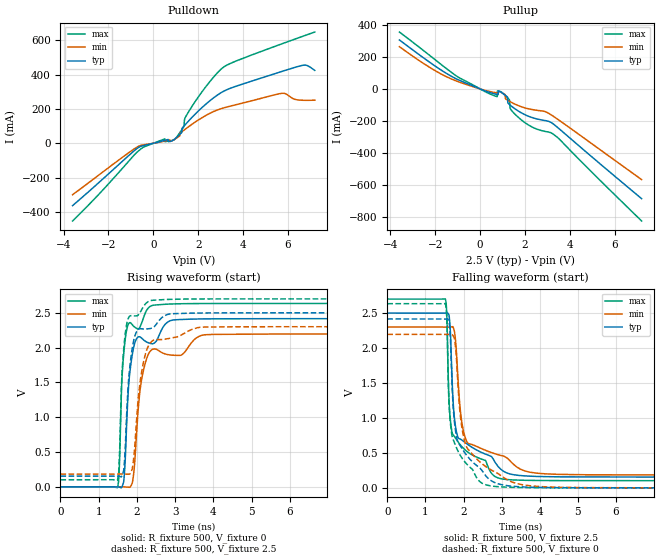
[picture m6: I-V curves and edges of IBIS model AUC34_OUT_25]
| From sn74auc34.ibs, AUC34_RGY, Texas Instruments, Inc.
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[Model]   AUC34_OUT_25
Model_type  Output
Vref =   0
Rref =   500
Cref =   30p
Vmeas =   1.25
| variable   typ   min   max
C_comp   3.5pF   NA   NA
| C_pullup   9.63pF   2.22pF   24.54pF
| C_pulldown   6.92pF   2.05pF   16.12pF
[Temperature Range]   40   100   -40
| Ambient temperature   25   85   -40
[Voltage range]   2.5   2.3   2.7
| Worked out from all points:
|   slope of the pulldown table from 0 to 0.375 V, typ, clamps not added: 30.7 ohm
|   slope of the pullup table from 0 to 0.375 V, typ, clamps not added: 19.1 ohm
|   rising waveform, R_fixture 500, V_fixture 0: 20-80 % time 187ps typ, 255ps min, 137ps max; typ from 0 V to 2.42 V
|   falling waveform, R_fixture 500, V_fixture 2.5: 20-80 % time 434ps typ, 457ps min, 329ps max; typ from 2.5 V to 0.155 V
|   rising waveform, R_fixture 500, V_fixture 2.5: 20-80 % time 190ps typ, 262ps min, 137ps max; typ from 0.154 V to 2.5 V
|   falling waveform, R_fixture 500, V_fixture 0: 20-80 % time 388ps typ, 478ps min, 277ps max; typ from 2.42 V to 0 V
[Pulldown]
| AUC34_OUT_25
|   Voltage   I(typ)   I(min)   I(max)
-3.6V     -363.3mA   -299.7mA   -452.8mA
-560mV    -17.97mA   -12.29mA   -33.51mA
510mV     17.07mA    12.84mA    25.87mA
975mV     26.82mA    25.47mA    25.82mA
1.27V     63.12mA    66.67mA    79.37mA
1.37V     100.7mA    76.6mA     99.34mA
1.42V     107.9mA    81.53mA    148.5mA
1.84V     166.6mA    121.2mA    238mA
3.1V      300.6mA    204.7mA    440.5mA
5.74V     418.9mA    291.2mA    579.9mA
6.745V    455.6mA    250.5mA    627.2mA
7.2V      424.9mA    251.1mA    648.3mA
[Pullup]
| AUC34_OUT_25
|   Voltage   I(typ)   I(min)   I(max)
-3.6V     305mA      263.2mA    354.5mA
-960mV    55.76mA    44.28mA    72.07mA
730mV     -33.82mA   -24.42mA   -47.21mA
760mV     -34.84mA   -25.13mA   -47.16mA
770mV     -35.18mA   -25.36mA   -13.25mA
980mV     -25.02mA   -24.81mA   -22.86mA
1.215V    -49.49mA   -69.56mA   -54.81mA
1.3V      -96.78mA   -76.45mA   -67.02mA
1.34V     -101.5mA   -79.57mA   -121.6mA
1.66V     -133.9mA   -101.4mA   -171.6mA
3.46V     -241mA     -189.3mA   -303.8mA
7.2V      -683.6mA   -565.1mA   -822.8mA
[Ramp]
| AUC34_OUT_25
| variable   typ   min   max
dV/dt_r   1.46/1.89E-10   1.32/2.58E-10   1.59/1.38E-10
dV/dt_f   1.41/4.34E-10   1.27/4.58E-10   1.56/3.30E-10
R_load = 500
[Rising Waveform]
| AUC34_OUT_25
R_fixture =   500
C_fixture =   0
L_fixture =   0
V_fixture =   0
V_fixture_min = 0
V_fixture_max = 0
|   Time   V(typ)   V(min)   V(max)
0s        13.01nV    39.01nV    2.017nV
1.49ns    -4.959uV   136uV      -10.96mV
1.655ns   75.05mV    861.7uV    1.908V
1.73ns    875.1mV    -2.556mV   2.247V
1.805ns   1.59V      -5.48mV    2.358V
1.95ns    2.075V     408.6mV    2.292V
2.115ns   2.141V     1.513V     2.34V
2.415ns   2.054V     1.978V     2.607V
3.35ns    2.408V     2.011V     2.631V
22ns      2.416V     2.195V     2.634V
[Falling Waveform]
| AUC34_OUT_25
R_fixture =   500
C_fixture =   0
L_fixture =   0
V_fixture =   2.5
V_fixture_min = 2.3
V_fixture_max = 2.7
|   Time   V(typ)   V(min)   V(max)
0s        2.5V       2.3V       2.7V
1.525ns   2.499V     2.3V       2.699V
1.565ns   2.501V     2.299V     2.403V
1.63ns    2.416V     2.298V     1.135V
1.705ns   1.468V     2.304V     777.4mV
1.82ns    786.1mV    1.887V     685.8mV
1.92ns    696mV      1.085V     612mV
2.055ns   642.9mV    700.2mV    536.6mV
2.975ns   266.4mV    464.2mV    131.3mV
22ns      154.5mV    184.4mV    102.7mV
[Rising Waveform]
| AUC34_OUT_25
R_fixture =   500
C_fixture =   0
L_fixture =   0
V_fixture =   2.5
V_fixture_min = 2.3
V_fixture_max = 2.7
|   Time   V(typ)   V(min)   V(max)
0s        154.5mV    184.4mV    102.6mV
1.49ns    154.5mV    184.5mV    92.74mV
1.53ns    153.7mV    184.6mV    269.4mV
1.6ns     150.5mV    185.4mV    1.505V
1.655ns   239.8mV    185.2mV    1.977V
1.73ns    1.019V     182.6mV    2.327V
1.935ns   2.145V     521.7mV    2.455V
2.095ns   2.272V     1.551V     2.517V
2.355ns   2.275V     2.071V     2.675V
22ns      2.5V       2.3V       2.7V
[Falling Waveform]
| AUC34_OUT_25
R_fixture =   500
C_fixture =   0
L_fixture =   0
V_fixture =   0
V_fixture_min = 0
V_fixture_max = 0
|   Time   V(typ)   V(min)   V(max)
0s        2.416V     2.195V     2.634V
1.525ns   2.414V     2.195V     2.632V
1.565ns   2.416V     2.194V     2.332V
1.63ns    2.327V     2.194V     1.095V
1.7ns     1.457V     2.193V     735.8mV
1.81ns    748.2mV    1.883V     578.1mV
1.905ns   609.7mV    1.091V     472.8mV
2.025ns   507.5mV    676.5mV    377.2mV
2.655ns   130.9mV    278.6mV    34.26mV
22ns      50.66uV    16.41uV    23.11uV
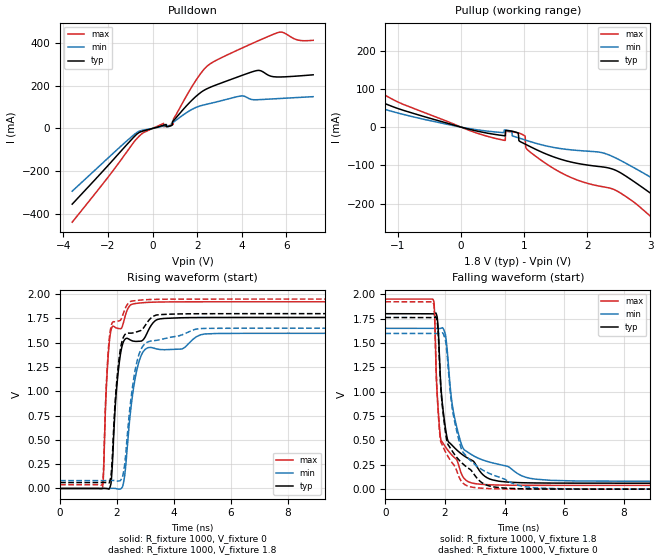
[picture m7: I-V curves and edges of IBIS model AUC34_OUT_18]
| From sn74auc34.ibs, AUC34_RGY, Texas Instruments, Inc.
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[Model]   AUC34_OUT_18
Model_type  Output
Vref =   0
Rref =   1000
Cref =   30p
Vmeas =   0.9
| variable   typ   min   max
C_comp   3.5pF   NA   NA
| C_pullup   8.40pF   1.40pF   22.32pF
| C_pulldown   6.69pF   0.86pF   15.74pF
[Temperature Range]   40   100   -40
| Ambient temperature   25   85   -40
[Voltage range]   1.8   1.65   1.95
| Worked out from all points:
|   slope of the pulldown table from 0 to 0.27 V, typ, clamps not added: 34.3 ohm
|   slope of the pullup table from 0 to 0.27 V, typ, clamps not added: 24.6 ohm
|   rising waveform, R_fixture 1000, V_fixture 0: 20-80 % time 282ps typ, 415ps min, 190ps max; typ from 0 V to 1.76 V
|   falling waveform, R_fixture 1000, V_fixture 1.8: 20-80 % time 570ps typ, 589ps min, 370ps max; typ from 1.8 V to 0.061 V
|   rising waveform, R_fixture 1000, V_fixture 1.8: 20-80 % time 280ps typ, 410ps min, 188ps max; typ from 0.061 V to 1.8 V
|   falling waveform, R_fixture 1000, V_fixture 0: 20-80 % time 528ps typ, 675ps min, 338ps max; typ from 1.76 V to 0 V
[Pulldown]
| AUC34_OUT_18
|   Voltage   I(typ)   I(min)   I(max)
-3.6V     -353mA     -292.5mA   -437.1mA
-555mV    -16.57mA   -11mA      -31.66mA
495mV     15.16mA    11.03mA    23.58mA
820mV     12.51mA    12.73mA    14.89mA
925mV     35.08mA    28.52mA    18.81mA
950mV     37.73mA    30.39mA    46.5mA
1.675V    122.4mA    83.44mA    179.3mA
2.51V     188.6mA    114.9mA    296mA
3.98V     246.3mA    151.7mA    373.5mA
4.685V    270.2mA    134mA      406.4mA
5.665V    240.1mA    139.5mA    448.4mA
7.2V      250.2mA    148.3mA    411mA
[Pullup]
| AUC34_OUT_18
|   Voltage   I(typ)   I(min)   I(max)
-3.6V     279.3mA    234.4mA    328.1mA
-2.85V    204.9mA    166.3mA    251mA
-1.38V    73.83mA    55.65mA    100.5mA
375mV     -14.45mA   -9.607mA   -22.05mA
940mV     -38.19mA   -29.59mA   -16.84mA
1.015V    -44.32mA   -33.6mA    -24.07mA
1.045V    -46.82mA   -35.18mA   -57.98mA
1.425V    -75.29mA   -51.77mA   -103.9mA
2.46V     -113.6mA   -81.44mA   -165.9mA
3.345V    -213mA     -163.7mA   -282.3mA
4.39V     -335.7mA   -266.5mA   -428.1mA
7.2V      -660.5mA   -545mA     -809.4mA
[Ramp]
| AUC34_OUT_18
| variable   typ   min   max
dV/dt_r   1.06/2.85E-10   0.96/4.18E-10   1.16/1.92E-10
dV/dt_f   1.05/5.66E-10   0.95/5.88E-10   1.15/3.70E-10
R_load = 1000
[Rising Waveform]
| AUC34_OUT_18
R_fixture =   1000
C_fixture =   0
L_fixture =   0
V_fixture =   0
V_fixture_min = 0
V_fixture_max = 0
|   Time   V(typ)   V(min)   V(max)
0s        10.21nV    35.63nV    1.217nV
1.485ns   443.4uV    -15.73uV   -1.029mV
1.63ns    -467.6uV   72.28uV    1.073V
1.765ns   24.21mV    1.02mV     1.593V
2.115ns   1.372V     -6.432mV   1.645V
2.27ns    1.533V     135.1mV    1.758V
2.54ns    1.52V      950mV      1.898V
2.985ns   1.557V     1.431V     1.914V
5.09ns    1.76V      1.591V     1.922V
22.5ns    1.761V     1.597V     1.922V
[Falling Waveform]
| AUC34_OUT_18
R_fixture =   1000
C_fixture =   0
L_fixture =   0
V_fixture =   1.8
V_fixture_min = 1.65
V_fixture_max = 1.95
|   Time   V(typ)   V(min)   V(max)
0s        1.8V       1.65V      1.95V
1.6ns     1.799V     1.65V      1.945V
1.645ns   1.801V     1.65V      1.839V
1.74ns    1.758V     1.649V     970.6mV
1.86ns    1.067V     1.651V     508.7mV
2.1ns     495.3mV    1.331V     397.3mV
2.4ns     400.6mV    629.1mV    299mV
2.87ns    301.1mV    358.2mV    66.02mV
5.54ns    62.55mV    90.61mV    39.07mV
22.5ns    61.11mV    81.04mV    38.71mV
[Rising Waveform]
| AUC34_OUT_18
R_fixture =   1000
C_fixture =   0
L_fixture =   0
V_fixture =   1.8
V_fixture_min = 1.65
V_fixture_max = 1.95
|   Time   V(typ)   V(min)   V(max)
0s        61.05mV    81.01mV    38.68mV
1.485ns   61.48mV    81mV       39.16mV
1.63ns    60.76mV    81.08mV    1.109V
1.76ns    89.4mV     81.91mV    1.622V
2.095ns   1.389V     78.86mV    1.728V
2.26ns    1.577V     228.6mV    1.833V
2.485ns   1.599V     912.6mV    1.927V
2.95ns    1.661V     1.481V     1.942V
4.87ns    1.799V     1.645V     1.95V
22.5ns    1.8V       1.65V      1.95V
[Falling Waveform]
| AUC34_OUT_18
R_fixture =   1000
C_fixture =   0
L_fixture =   0
V_fixture =   0
V_fixture_min = 0
V_fixture_max = 0
|   Time   V(typ)   V(min)   V(max)
0s        1.761V     1.597V     1.922V
1.6ns     1.76V      1.597V     1.917V
1.645ns   1.762V     1.597V     1.809V
1.74ns    1.716V     1.596V     952.5mV
1.855ns   1.062V     1.598V     488.9mV
2.09ns    464.6mV    1.312V     340.4mV
2.39ns    327.9mV    599.5mV    191.5mV
2.825ns   206.3mV    302.8mV    26.23mV
5.225ns   1.836mV    10.38mV    473.2uV
22.5ns    59.83uV    23.9uV     25.9uV
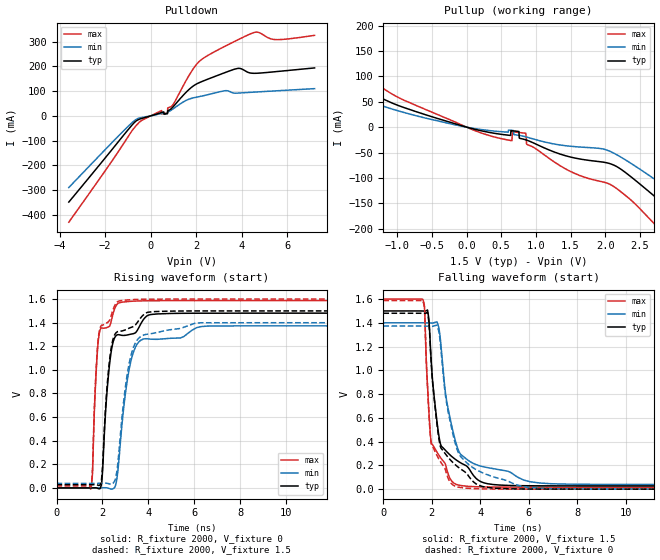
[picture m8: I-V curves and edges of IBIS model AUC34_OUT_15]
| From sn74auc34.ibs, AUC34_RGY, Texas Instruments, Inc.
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[Model]   AUC34_OUT_15
Model_type  Output
Vref =   0
Rref =   2000
Cref =   15p
Vmeas =   0.75
| variable   typ   min   max
C_comp   3.5pF   NA   NA
| C_pullup   7.01pF   2.00pF   19.70pF
| C_pulldown   7.08pF   4.51pF   15.46pF
[Temperature Range]   40   100   -40
| Ambient temperature   25   85   -40
[Voltage range]   1.5   1.4   1.6
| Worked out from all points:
|   slope of the pulldown table from 0 to 0.225 V, typ, clamps not added: 37.3 ohm
|   slope of the pullup table from 0 to 0.225 V, typ, clamps not added: 29.6 ohm
|   rising waveform, R_fixture 2000, V_fixture 0: 20-80 % time 363ps typ, 536ps min, 238ps max; typ from 0 V to 1.48 V
|   falling waveform, R_fixture 2000, V_fixture 1.5: 20-80 % time 645ps typ, 723ps min, 412ps max; typ from 1.5 V to 0.027 V
|   rising waveform, R_fixture 2000, V_fixture 1.5: 20-80 % time 358ps typ, 528ps min, 234ps max; typ from 0.027 V to 1.5 V
|   falling waveform, R_fixture 2000, V_fixture 0: 20-80 % time 623ps typ, 782ps min, 391ps max; typ from 1.48 V to 0 V
[Pulldown]
| AUC34_OUT_15
|   Voltage   I(typ)   I(min)   I(max)
-3.6V     -348.4mA   -289.5mA   -429.6mA
-665mV    -22.33mA   -15.81mA   -42.01mA
480mV     13.54mA    9.64mA     21.5mA
735mV     9.284mA    14.92mA    12.28mA
750mV     20.66mA    15.42mA    31.62mA
980mV     36.38mA    28.08mA    45.45mA
1.775V    114mA      70.34mA    177.1mA
2.235V    138.2mA    79.83mA    227.7mA
3.81V     191.5mA    91.9mA     306.5mA
4.58V     172mA      96.1mA     337.9mA
5.485V    178.5mA    101mA      308.2mA
7.2V      193.7mA    110mA      325.3mA
[Pullup]
| AUC34_OUT_15
|   Voltage   I(typ)   I(min)   I(max)
-3.6V     266mA      208.2mA    314.3mA
-2.885V   197.2mA    157.7mA    242.1mA
-2.5V     161mA      126.6mA    203.2mA
-900mV    38.43mA    28.74mA    52.85mA
390mV     -11.89mA   -7.641mA   -18.98mA
855mV     -25.04mA   -19.21mA   -12.06mA
870mV     -25.74mA   -19.76mA   -33.77mA
1.35V     -53.08mA   -35.2mA    -76.07mA
2.125V    -74.89mA   -51.34mA   -117.2mA
2.825V    -149.3mA   -113mA     -207mA
3.65V     -245.1mA   -192.4mA   -322.4mA
7.2V      -652.9mA   -541.5mA   -802.5mA
[Ramp]
| AUC34_OUT_15
| variable   typ   min   max
dV/dt_r   0.89/3.65E-10   0.83/5.40E-10   0.96/2.39E-10
dV/dt_f   0.89/6.40E-10   0.82/7.26E-10   0.95/4.12E-10
R_load = 2000
[Rising Waveform]
| AUC34_OUT_15
R_fixture =   2000
C_fixture =   0
L_fixture =   0
V_fixture =   0
V_fixture_min = 0
V_fixture_max = 0
|   Time   V(typ)   V(min)   V(max)
0s        9.392nV    35.9nV     957pV
1.5ns     63.26uV    -10.33uV   -7.682mV
1.565ns   318.5uV    -15.07uV   119.7mV
1.755ns   -265.4uV   6.717uV    1.079V
1.92ns    3.978mV    708.6uV    1.348V
2.33ns    1.079V     -6.997mV   1.378V
2.72ns    1.298V     237.8mV    1.567V
3.185ns   1.3V       1.025V     1.58V
3.775ns   1.424V     1.261V     1.585V
22.2ns    1.481V     1.373V     1.587V
[Falling Waveform]
| AUC34_OUT_15
R_fixture =   2000
C_fixture =   0
L_fixture =   0
V_fixture =   1.5
V_fixture_min = 1.4
V_fixture_max = 1.6
|   Time   V(typ)   V(min)   V(max)
0s        1.5V       1.4V       1.6V
1.63ns    1.499V     1.4V       1.596V
1.695ns   1.499V     1.4V       1.535V
1.835ns   1.493V     1.399V     816.7mV
1.975ns   1.078V     1.398V     395mV
2.35ns    384.7mV    1.265V     268.6mV
2.595ns   319.7mV    764.2mV    184mV
3.025ns   243.1mV    369.5mV    39.23mV
6.495ns   28.21mV    51.13mV    16.65mV
22.2ns    27.24mV    38.79mV    16.43mV
[Rising Waveform]
| AUC34_OUT_15
R_fixture =   2000
C_fixture =   0
L_fixture =   0
V_fixture =   1.5
V_fixture_min = 1.4
V_fixture_max = 1.6
|   Time   V(typ)   V(min)   V(max)
0s        27.17mV    38.75mV    16.4mV
1.5ns     27.23mV    38.74mV    9.342mV
1.565ns   27.48mV    38.74mV    143.2mV
1.75ns    27.27mV    38.75mV    1.089V
1.905ns   28.67mV    39.33mV    1.361V
2.325ns   1.106V     33.06mV    1.426V
2.705ns   1.326V     273.2mV    1.582V
3.185ns   1.355V     1.074V     1.594V
3.82ns    1.472V     1.297V     1.598V
22.2ns    1.5V       1.4V       1.6V
[Falling Waveform]
| AUC34_OUT_15
R_fixture =   2000
C_fixture =   0
L_fixture =   0
V_fixture =   0
V_fixture_min = 0
V_fixture_max = 0
|   Time   V(typ)   V(min)   V(max)
0s        1.481V     1.373V     1.587V
1.63ns    1.48V      1.373V     1.583V
1.695ns   1.48V      1.373V     1.521V
1.835ns   1.472V     1.372V     805.2mV
1.97ns    1.075V     1.371V     387.1mV
2.345ns   364.3mV    1.242V     235mV
2.585ns   290.2mV    756.8mV    144.2mV
2.98ns    203.4mV    374.9mV    23.74mV
6.09ns    1.291mV    13mV       305.8uV
22.2ns    70.2uV     36.25uV    29.94uV
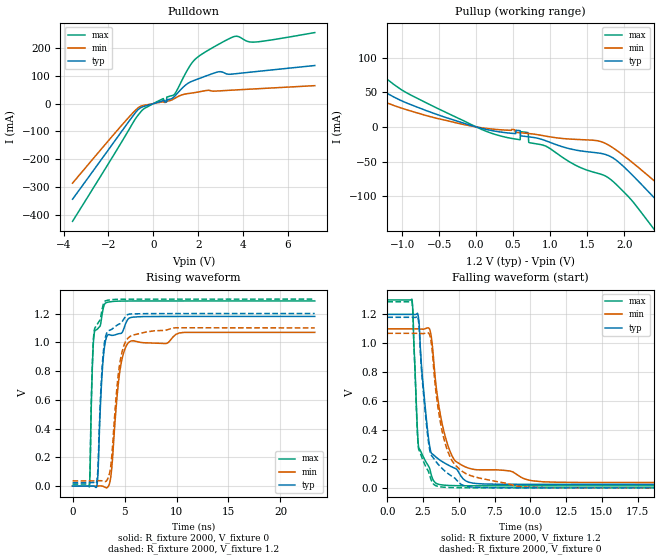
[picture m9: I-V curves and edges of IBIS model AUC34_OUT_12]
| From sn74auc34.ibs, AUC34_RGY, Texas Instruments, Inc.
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[Model]   AUC34_OUT_12
Model_type  Output
Vref =   0
Rref =   2000
Cref =   15p
Vmeas =   0.6
| variable   typ   min   max
C_comp   3.5pF   NA   NA
| C_pullup   6.25pF   0.87pF   16.76pF
| C_pulldown   6.74pF   4.64pF   15.17pF
[Temperature Range]   40   100   -40
| Ambient temperature   25   85   -40
[Voltage range]   1.2   1.1   1.3
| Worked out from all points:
|   slope of the pulldown table from 0 to 0.18 V, typ, clamps not added: 41.6 ohm
|   slope of the pullup table from 0 to 0.18 V, typ, clamps not added: 38.4 ohm
|   rising waveform, R_fixture 2000, V_fixture 0: 20-80 % time 512ps typ, 815ps min, 312ps max; typ from 0 V to 1.18 V
|   falling waveform, R_fixture 2000, V_fixture 1.2: 20-80 % time 707ps typ, 1.16ns min, 378ps max; typ from 1.2 V to 0.024 V
|   rising waveform, R_fixture 2000, V_fixture 1.2: 20-80 % time 501ps typ, 807ps min, 305ps max; typ from 0.024 V to 1.2 V
|   falling waveform, R_fixture 2000, V_fixture 0: 20-80 % time 722ps typ, 1.17ns min, 394ps max; typ from 1.18 V to 0 V
[Pulldown]
| AUC34_OUT_12
|   Voltage   I(typ)   I(min)   I(max)
-3.6V     -343.7mA   -285.9mA   -423.2mA
-650mV    -19.7mA    -13.52mA   -38.65mA
-370mV    -8.898mA   -5.454mA   -16.13mA
590mV     6.193mA    8.414mA    8.677mA
605mV     13.32mA    8.578mA    23.51mA
930mV     24.77mA    17.77mA    32.46mA
1.61V     76.08mA    36.87mA    132.9mA
1.985V    88.47mA    41.53mA    167.6mA
2.92V     114.6mA    45.74mA    213.7mA
3.635V    107.2mA    49.01mA    241.8mA
4.51V     114.7mA    52.9mA     221.3mA
7.2V      137mA      64.62mA    255.5mA
[Pullup]
| AUC34_OUT_12
|   Voltage   I(typ)   I(min)   I(max)
-3.6V     236.7mA    114.8mA    301.3mA
-2.45V    144.6mA    76.08mA    187.3mA
-2.055V   110.8mA    79.63mA    148.3mA
-675mV    23.63mA    16.44mA    34.85mA
270mV     -6.37mA    -3.622mA   -11.25mA
700mV     -14.19mA   -9.421mA   -8.122mA
715mV     -14.38mA   -9.579mA   -22.55mA
1.785V    -41.24mA   -25.95mA   -73.29mA
2.43V     -105mA     -79.97mA   -151.5mA
2.8V      -147.1mA   -114.5mA   -203.3mA
3.29V     -203.3mA   -161.3mA   -270.8mA
7.2V      -648.3mA   -542.2mA   -796.5mA
[Ramp]
| AUC34_OUT_12
| variable   typ   min   max
dV/dt_r   0.71/5.13E-10   0.65/8.19E-10   0.78/3.16E-10
dV/dt_f   0.71/7.13E-10   0.64/1.17E-09   0.78/3.83E-10
R_load = 2000
[Rising Waveform]
| AUC34_OUT_12
R_fixture =   2000
C_fixture =   0
L_fixture =   0
V_fixture =   0
V_fixture_min = 0
V_fixture_max = 0
|   Time   V(typ)   V(min)   V(max)
0s        8.805nV    38.15nV    771.5pV
1.625ns   -16.56uV   -3.729uV   -5.943mV
1.97ns    1.203mV    -31.58uV   950.2mV
2.325ns   -2.323mV   478.3uV    1.088V
2.82ns    756.5mV    935.3uV    1.181V
3.185ns   1.015V     -10.15mV   1.273V
3.695ns   1.049V     74.65mV    1.282V
4.61ns    1.061V     827mV      1.286V
5.47ns    1.169V     1.003V     1.287V
23.3ns    1.18V      1.069V     1.287V
[Falling Waveform]
| AUC34_OUT_12
R_fixture =   2000
C_fixture =   0
L_fixture =   0
V_fixture =   1.2
V_fixture_min = 1.1
V_fixture_max = 1.3
|   Time   V(typ)   V(min)   V(max)
0s        1.2V       1.1V       1.3V
1.725ns   1.2V       1.1V       1.304V
2.18ns    1.177V     1.1V       286.3mV
2.425ns   798.6mV    1.098V     233.4mV
2.87ns    350.9mV    1.107V     152.9mV
3.09ns    238.8mV    1.035V     84.62mV
3.42ns    211.8mV    696.3mV    31.04mV
4.375ns   151.5mV    255.1mV    16.38mV
5.67ns    39.85mV    136.8mV    14.4mV
23.3ns    24.06mV    36.69mV    13.89mV
[Rising Waveform]
| AUC34_OUT_12
R_fixture =   2000
C_fixture =   0
L_fixture =   0
V_fixture =   1.2
V_fixture_min = 1.1
V_fixture_max = 1.3
|   Time   V(typ)   V(min)   V(max)
0s        23.98mV    36.61mV    13.86mV
1.625ns   23.96mV    36.6mV     10.5mV
1.96ns    25.08mV    36.58mV    958.1mV
2.31ns    26.79mV    37.01mV    1.117V
2.795ns   768mV      37.36mV    1.211V
3.115ns   1.019V     32.08mV    1.286V
3.67ns    1.087V     138.1mV    1.295V
4.585ns   1.13V      871.9mV    1.299V
5.48ns    1.196V     1.038V     1.3V
23.3ns    1.2V       1.1V       1.3V
[Falling Waveform]
| AUC34_OUT_12
R_fixture =   2000
C_fixture =   0
L_fixture =   0
V_fixture =   0
V_fixture_min = 0
V_fixture_max = 0
|   Time   V(typ)   V(min)   V(max)
0s        1.18V      1.069V     1.287V
1.725ns   1.18V      1.069V     1.291V
2.17ns    1.16V      1.069V     279.2mV
2.42ns    777.2mV    1.067V     208.9mV
2.83ns    354mV      1.073V     122mV
3.065ns   227.6mV    1.008V     55.14mV
3.34ns    190mV      718.7mV    17.78mV
4.245ns   98.72mV    248mV      2.771mV
5.785ns   6.77mV     85.82mV    465.5uV
23.3ns    81.17uV    60.68uV    31.54uV
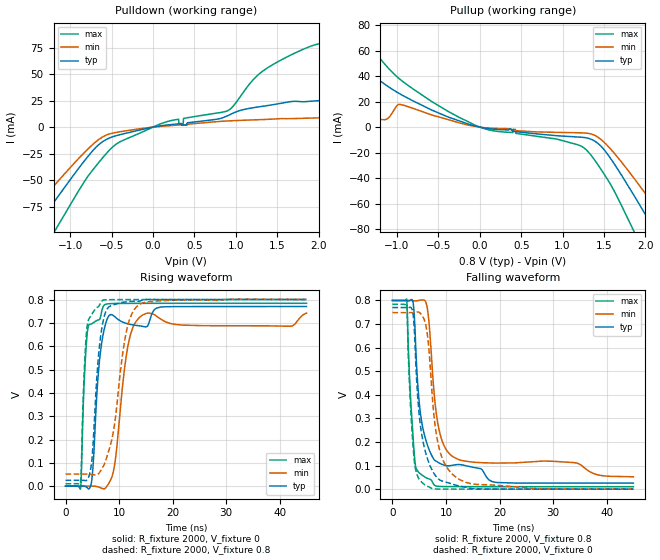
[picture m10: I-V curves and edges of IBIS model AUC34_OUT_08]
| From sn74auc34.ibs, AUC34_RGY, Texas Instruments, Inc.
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[Model]   AUC34_OUT_08
Model_type  Output
Vref =   0
Rref =   2000
Cref =   15p
Vmeas =   0.4
| variable   typ   min   max
C_comp   3.5pF   NA   NA
| C_pullup   5.60pF   2.30pF   8.11pF
| C_pulldown   6.44pF   5.86pF   6.78pF
[Temperature Range]   40   100   -40
| Ambient temperature   25   85   -40
[Voltage range]   0.8   0.8   0.8
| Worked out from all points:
|   slope of the pulldown table from 0 to 0.12 V, typ, clamps not added: 76.3 ohm
|   slope of the pullup table from 0 to 0.12 V, typ, clamps not added: 91.4 ohm
|   rising waveform, R_fixture 2000, V_fixture 0: 20-80 % time 1.46ns typ, 2.11ns min, 869ps max; typ from 0 V to 0.77 V
|   falling waveform, R_fixture 2000, V_fixture 0.8: 20-80 % time 2.36ns typ, 2.3ns min, 1.1ns max; typ from 0.8 V to 0.026 V
|   rising waveform, R_fixture 2000, V_fixture 0.8: 20-80 % time 1.43ns typ, 2.6ns min, 811ps max; typ from 0.025 V to 0.8 V
|   falling waveform, R_fixture 2000, V_fixture 0: 20-80 % time 2ns typ, 2.23ns min, 1.05ns max; typ from 0.77 V to 0 V
[Pulldown]
| AUC34_OUT_08
|   Voltage   I(typ)   I(min)   I(max)
-3.6V     -337.3mA   -282.2mA   -412.4mA
-1.79V    -136.5mA   -110mA     -177.8mA
-1.39V    -92.23mA   -73.02mA   -125.2mA
-1.17V    -68.14mA   -53.2mA    -96.14mA
-685mV    -18.8mA    -13.58mA   -36.41mA
-430mV    -7.788mA   -4.787mA   -15.34mA
165mV     1.975mA    1.123mA    5.083mA
905mV     10.9mA     5.849mA    15.59mA
1.32V     19.64mA    7.147mA    52.55mA
2.005V    25.03mA    8.767mA    78.7mA
3.335V    32.94mA    11.65mA    90.33mA
7.2V      56.65mA    21.1mA     140.7mA
[Pullup]
| AUC34_OUT_08
|   Voltage   I(typ)   I(min)   I(max)
-3.6V     112.9mA    15.55mA    196mA
-2.685V   76.06mA    17.84mA    164mA
-1.875V   36.81mA    19.48mA    111.1mA
-1.505V   32.64mA    11.52mA    78.71mA
-1.285V   39.44mA    7.211mA    60.37mA
-960mV    25.93mA    17.8mA     37.34mA
-245mV    4.855mA    3.296mA    7.535mA
1.26V     -8.135mA   -4.57mA    -16.37mA
1.87V     -54.47mA   -40.74mA   -82.92mA
2.04V     -72.97mA   -55.67mA   -106mA
2.465V    -120.2mA   -94.46mA   -163.4mA
7.2V      -650.8mA   -549.9mA   -789.4mA
[Ramp]
| AUC34_OUT_08
| variable   typ   min   max
dV/dt_r   0.47/1.46E-09   0.45/2.13E-09   0.48/8.71E-10
dV/dt_f   0.47/2.35E-09   0.45/2.29E-09   0.48/1.10E-09
R_load = 2000
[Rising Waveform]
| AUC34_OUT_08
R_fixture =   2000
C_fixture =   0
L_fixture =   0
V_fixture =   0
V_fixture_min = 0
V_fixture_max = 0
|   Time   V(typ)   V(min)   V(max)
0s        10.85nV    62.38nV    582.1pV
2.835ns   630uV      -66.09uV   -4.681mV
3.765ns   -1.879mV   579.1uV    571.5mV
4.755ns   7.536mV    642.7uV    694.9mV
6.17ns    497.6mV    -3.473mV   712.7mV
7.29ns    679.6mV    -10.93mV   777.5mV
9.15ns    727.1mV    89.92mV    783mV
11.76ns   695.2mV    614.9mV    783.4mV
13.88ns   687mV      725.4mV    783.6mV
45ns      770mV      741.8mV    783.7mV
[Falling Waveform]
| AUC34_OUT_08
R_fixture =   2000
C_fixture =   0
L_fixture =   0
V_fixture =   0.8
V_fixture_min = 0.8
V_fixture_max = 0.8
|   Time   V(typ)   V(min)   V(max)
0s        800mV      800mV      800mV
2.65ns    799.6mV    800.1mV    805.9mV
3.79ns    798.4mV    798.6mV    241.9mV
4.3ns     631.1mV    798.1mV    98.49mV
5.01ns    365.8mV    800.7mV    68.91mV
6.405ns   195.9mV    779.7mV    47.1mV
7.86ns    123.2mV    387.2mV    16.51mV
9.385ns   103.9mV    197.9mV    11.2mV
12.25ns   104.7mV    126.6mV    10.78mV
45ns      25.56mV    52.55mV    10.62mV
[Rising Waveform]
| AUC34_OUT_08
R_fixture =   2000
C_fixture =   0
L_fixture =   0
V_fixture =   0.8
V_fixture_min = 0.8
V_fixture_max = 0.8
|   Time   V(typ)   V(min)   V(max)
0s        25.46mV    51.93mV    10.6mV
2.795ns   25.9mV     51.92mV    15.96mV
3.66ns    24.08mV    52.19mV    572.4mV
4.495ns   53.42mV    51mV       721.7mV
6.09ns    543.9mV    52.42mV    769.1mV
6.87ns    689.9mV    78.76mV    795.6mV
8.885ns   776.8mV    228mV      799.4mV
11.41ns   790.6mV    669.2mV    799.7mV
13.52ns   791.7mV    774.1mV    799.8mV
45ns      800mV      800.2mV    800mV
[Falling Waveform]
| AUC34_OUT_08
R_fixture =   2000
C_fixture =   0
L_fixture =   0
V_fixture =   0
V_fixture_min = 0
V_fixture_max = 0
|   Time   V(typ)   V(min)   V(max)
0s        770mV      748.6mV    783.8mV
2.645ns   769.7mV    748.6mV    786.7mV
3.22ns    771mV      748.4mV    425.3mV
3.755ns   756.9mV    748.4mV    213.5mV
4.875ns   345.1mV    750.8mV    46.84mV
5.945ns   177.7mV    718.3mV    20.03mV
6.645ns   122.2mV    631.4mV    11.32mV
8.425ns   46.93mV    204.3mV    629.3uV
11.68ns   18.16mV    54.16mV    174.6uV
45ns      70.31uV    33.66uV    21.37uV
